VERSION 5.7 ;
  NOWIREEXTENSIONATPIN ON ;
  DIVIDERCHAR "/" ;
  BUSBITCHARS "[]" ;
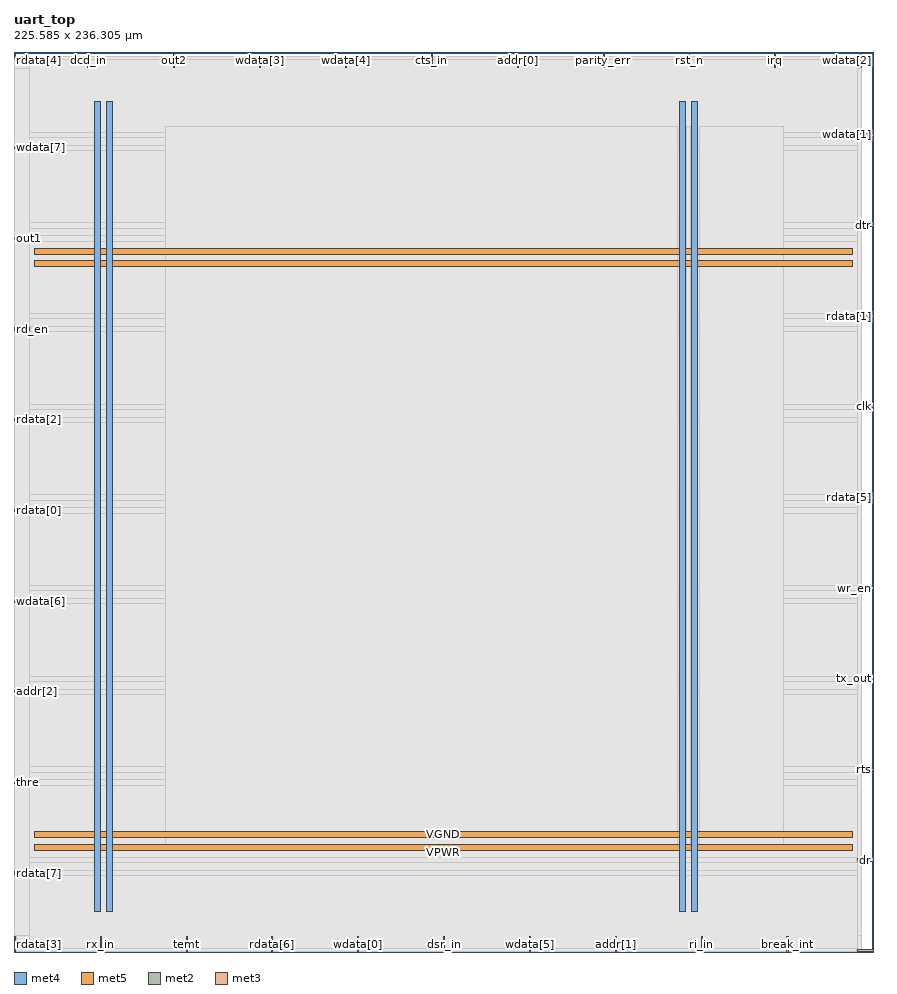
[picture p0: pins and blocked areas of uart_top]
MACRO uart_top
  CLASS BLOCK ;
  FOREIGN uart_top ;
  ORIGIN 0.000 0.000 ;
  SIZE 225.585 BY 236.305 ;
  PIN VGND
    DIRECTION INOUT ;
    USE GROUND ;
    PORT
      LAYER met4 ;
        RECT 24.340 10.640 25.940 223.280 ;
    END
    PORT
      LAYER met4 ;
        RECT 177.940 10.640 179.540 223.280 ;
    END
    PORT
      LAYER met5 ;
        RECT 5.280 30.030 220.120 31.630 ;
    END
    PORT
      LAYER met5 ;
        RECT 5.280 183.210 220.120 184.810 ;
    END
  END VGND
  PIN VPWR
    DIRECTION INOUT ;
    USE POWER ;
    PORT
      LAYER met4 ;
        RECT 21.040 10.640 22.640 223.280 ;
    END
    PORT
      LAYER met4 ;
        RECT 174.640 10.640 176.240 223.280 ;
    END
    PORT
      LAYER met5 ;
        RECT 5.280 26.730 220.120 28.330 ;
    END
    PORT
      LAYER met5 ;
        RECT 5.280 179.910 220.120 181.510 ;
    END
  END VPWR
  PIN addr[0]
    DIRECTION INPUT ;
    USE SIGNAL ;
    ANTENNAGATEAREA 0.159000 ;
    PORT
      LAYER met2 ;
        RECT 132.110 232.305 132.390 236.305 ;
    END
  END addr[0]
  PIN addr[1]
    DIRECTION INPUT ;
    USE SIGNAL ;
    ANTENNAGATEAREA 0.213000 ;
    PORT
      LAYER met2 ;
        RECT 157.870 0.000 158.150 4.000 ;
    END
  END addr[1]
  PIN addr[2]
    DIRECTION INPUT ;
    USE SIGNAL ;
    ANTENNAGATEAREA 0.159000 ;
    PORT
      LAYER met3 ;
        RECT 0.000 68.040 4.000 68.640 ;
    END
  END addr[2]
  PIN break_int
    DIRECTION OUTPUT TRISTATE ;
    USE SIGNAL ;
    ANTENNADIFFAREA 0.795200 ;
    PORT
      LAYER met2 ;
        RECT 202.950 0.000 203.230 4.000 ;
    END
  END break_int
  PIN clk
    DIRECTION INPUT ;
    USE SIGNAL ;
    ANTENNAGATEAREA 0.852000 ;
    PORT
      LAYER met3 ;
        RECT 221.585 142.840 225.585 143.440 ;
    END
  END clk
  PIN cts_in
    DIRECTION INPUT ;
    USE SIGNAL ;
    PORT
      LAYER met2 ;
        RECT 109.570 232.305 109.850 236.305 ;
    END
  END cts_in
  PIN dcd_in
    DIRECTION INPUT ;
    USE SIGNAL ;
    PORT
      LAYER met2 ;
        RECT 19.410 232.305 19.690 236.305 ;
    END
  END dcd_in
  PIN dr
    DIRECTION OUTPUT TRISTATE ;
    USE SIGNAL ;
    ANTENNADIFFAREA 0.445500 ;
    PORT
      LAYER met3 ;
        RECT 221.585 23.840 225.585 24.440 ;
    END
  END dr
  PIN dsr_in
    DIRECTION INPUT ;
    USE SIGNAL ;
    PORT
      LAYER met2 ;
        RECT 112.790 0.000 113.070 4.000 ;
    END
  END dsr_in
  PIN dtr
    DIRECTION OUTPUT TRISTATE ;
    USE SIGNAL ;
    ANTENNADIFFAREA 0.445500 ;
    PORT
      LAYER met3 ;
        RECT 221.585 190.440 225.585 191.040 ;
    END
  END dtr
  PIN framing_err
    DIRECTION OUTPUT TRISTATE ;
    USE SIGNAL ;
    ANTENNADIFFAREA 0.795200 ;
    PORT
      LAYER met3 ;
        RECT 221.585 0.040 225.585 0.640 ;
    END
  END framing_err
  PIN irq
    DIRECTION OUTPUT TRISTATE ;
    USE SIGNAL ;
    ANTENNADIFFAREA 0.795200 ;
    PORT
      LAYER met2 ;
        RECT 199.730 232.305 200.010 236.305 ;
    END
  END irq
  PIN out1
    DIRECTION OUTPUT TRISTATE ;
    USE SIGNAL ;
    ANTENNADIFFAREA 0.795200 ;
    PORT
      LAYER met3 ;
        RECT 0.000 187.040 4.000 187.640 ;
    END
  END out1
  PIN out2
    DIRECTION OUTPUT TRISTATE ;
    USE SIGNAL ;
    ANTENNADIFFAREA 0.795200 ;
    PORT
      LAYER met2 ;
        RECT 41.950 232.305 42.230 236.305 ;
    END
  END out2
  PIN parity_err
    DIRECTION OUTPUT TRISTATE ;
    USE SIGNAL ;
    ANTENNADIFFAREA 0.795200 ;
    PORT
      LAYER met2 ;
        RECT 154.650 232.305 154.930 236.305 ;
    END
  END parity_err
  PIN rd_en
    DIRECTION INPUT ;
    USE SIGNAL ;
    ANTENNAGATEAREA 0.213000 ;
    PORT
      LAYER met3 ;
        RECT 0.000 163.240 4.000 163.840 ;
    END
  END rd_en
  PIN rdata[0]
    DIRECTION OUTPUT TRISTATE ;
    USE SIGNAL ;
    ANTENNADIFFAREA 0.795200 ;
    PORT
      LAYER met3 ;
        RECT 0.000 115.640 4.000 116.240 ;
    END
  END rdata[0]
  PIN rdata[1]
    DIRECTION OUTPUT TRISTATE ;
    USE SIGNAL ;
    ANTENNADIFFAREA 0.445500 ;
    PORT
      LAYER met3 ;
        RECT 221.585 166.640 225.585 167.240 ;
    END
  END rdata[1]
  PIN rdata[2]
    DIRECTION OUTPUT TRISTATE ;
    USE SIGNAL ;
    ANTENNADIFFAREA 0.795200 ;
    PORT
      LAYER met3 ;
        RECT 0.000 139.440 4.000 140.040 ;
    END
  END rdata[2]
  PIN rdata[3]
    DIRECTION OUTPUT TRISTATE ;
    USE SIGNAL ;
    ANTENNADIFFAREA 0.795200 ;
    PORT
      LAYER met2 ;
        RECT 0.090 0.000 0.370 4.000 ;
    END
  END rdata[3]
  PIN rdata[4]
    DIRECTION OUTPUT TRISTATE ;
    USE SIGNAL ;
    ANTENNADIFFAREA 0.795200 ;
    PORT
      LAYER met3 ;
        RECT 0.000 234.640 4.000 235.240 ;
    END
  END rdata[4]
  PIN rdata[5]
    DIRECTION OUTPUT TRISTATE ;
    USE SIGNAL ;
    ANTENNADIFFAREA 0.445500 ;
    PORT
      LAYER met3 ;
        RECT 221.585 119.040 225.585 119.640 ;
    END
  END rdata[5]
  PIN rdata[6]
    DIRECTION OUTPUT TRISTATE ;
    USE SIGNAL ;
    ANTENNADIFFAREA 0.795200 ;
    PORT
      LAYER met2 ;
        RECT 67.710 0.000 67.990 4.000 ;
    END
  END rdata[6]
  PIN rdata[7]
    DIRECTION OUTPUT TRISTATE ;
    USE SIGNAL ;
    ANTENNADIFFAREA 0.795200 ;
    PORT
      LAYER met3 ;
        RECT 0.000 20.440 4.000 21.040 ;
    END
  END rdata[7]
  PIN ri_in
    DIRECTION INPUT ;
    USE SIGNAL ;
    PORT
      LAYER met2 ;
        RECT 180.410 0.000 180.690 4.000 ;
    END
  END ri_in
  PIN rst_n
    DIRECTION INPUT ;
    USE SIGNAL ;
    ANTENNAGATEAREA 0.213000 ;
    PORT
      LAYER met2 ;
        RECT 177.190 232.305 177.470 236.305 ;
    END
  END rst_n
  PIN rts
    DIRECTION OUTPUT TRISTATE ;
    USE SIGNAL ;
    ANTENNADIFFAREA 0.445500 ;
    PORT
      LAYER met3 ;
        RECT 221.585 47.640 225.585 48.240 ;
    END
  END rts
  PIN rx_in
    DIRECTION INPUT ;
    USE SIGNAL ;
    ANTENNAGATEAREA 0.213000 ;
    PORT
      LAYER met2 ;
        RECT 22.630 0.000 22.910 4.000 ;
    END
  END rx_in
  PIN temt
    DIRECTION OUTPUT TRISTATE ;
    USE SIGNAL ;
    ANTENNADIFFAREA 0.795200 ;
    PORT
      LAYER met2 ;
        RECT 45.170 0.000 45.450 4.000 ;
    END
  END temt
  PIN thre
    DIRECTION OUTPUT TRISTATE ;
    USE SIGNAL ;
    ANTENNADIFFAREA 0.795200 ;
    PORT
      LAYER met3 ;
        RECT 0.000 44.240 4.000 44.840 ;
    END
  END thre
  PIN tx_out
    DIRECTION OUTPUT TRISTATE ;
    USE SIGNAL ;
    ANTENNADIFFAREA 0.445500 ;
    PORT
      LAYER met3 ;
        RECT 221.585 71.440 225.585 72.040 ;
    END
  END tx_out
  PIN wdata[0]
    DIRECTION INPUT ;
    USE SIGNAL ;
    ANTENNAGATEAREA 0.159000 ;
    PORT
      LAYER met2 ;
        RECT 90.250 0.000 90.530 4.000 ;
    END
  END wdata[0]
  PIN wdata[1]
    DIRECTION INPUT ;
    USE SIGNAL ;
    ANTENNAGATEAREA 0.213000 ;
    PORT
      LAYER met3 ;
        RECT 221.585 214.240 225.585 214.840 ;
    END
  END wdata[1]
  PIN wdata[2]
    DIRECTION INPUT ;
    USE SIGNAL ;
    ANTENNAGATEAREA 0.213000 ;
    PORT
      LAYER met2 ;
        RECT 222.270 232.305 222.550 236.305 ;
    END
  END wdata[2]
  PIN wdata[3]
    DIRECTION INPUT ;
    USE SIGNAL ;
    ANTENNAGATEAREA 0.213000 ;
    PORT
      LAYER met2 ;
        RECT 64.490 232.305 64.770 236.305 ;
    END
  END wdata[3]
  PIN wdata[4]
    DIRECTION INPUT ;
    USE SIGNAL ;
    ANTENNAGATEAREA 0.213000 ;
    PORT
      LAYER met2 ;
        RECT 87.030 232.305 87.310 236.305 ;
    END
  END wdata[4]
  PIN wdata[5]
    DIRECTION INPUT ;
    USE SIGNAL ;
    ANTENNAGATEAREA 0.159000 ;
    PORT
      LAYER met2 ;
        RECT 135.330 0.000 135.610 4.000 ;
    END
  END wdata[5]
  PIN wdata[6]
    DIRECTION INPUT ;
    USE SIGNAL ;
    ANTENNAGATEAREA 0.213000 ;
    PORT
      LAYER met3 ;
        RECT 0.000 91.840 4.000 92.440 ;
    END
  END wdata[6]
  PIN wdata[7]
    DIRECTION INPUT ;
    USE SIGNAL ;
    ANTENNAGATEAREA 0.213000 ;
    PORT
      LAYER met3 ;
        RECT 0.000 210.840 4.000 211.440 ;
    END
  END wdata[7]
  PIN wr_en
    DIRECTION INPUT ;
    USE SIGNAL ;
    ANTENNAGATEAREA 0.213000 ;
    PORT
      LAYER met3 ;
        RECT 221.585 95.240 225.585 95.840 ;
    END
  END wr_en
  OBS
      LAYER li1 ;
        RECT 5.520 10.795 219.880 223.125 ;
      LAYER met1 ;
        RECT 0.070 10.640 222.570 223.280 ;
      LAYER met2 ;
        RECT 0.100 232.025 19.130 235.125 ;
        RECT 19.970 232.025 41.670 235.125 ;
        RECT 42.510 232.025 64.210 235.125 ;
        RECT 65.050 232.025 86.750 235.125 ;
        RECT 87.590 232.025 109.290 235.125 ;
        RECT 110.130 232.025 131.830 235.125 ;
        RECT 132.670 232.025 154.370 235.125 ;
        RECT 155.210 232.025 176.910 235.125 ;
        RECT 177.750 232.025 199.450 235.125 ;
        RECT 200.290 232.025 221.990 235.125 ;
        RECT 0.100 4.280 222.540 232.025 ;
        RECT 0.650 0.155 22.350 4.280 ;
        RECT 23.190 0.155 44.890 4.280 ;
        RECT 45.730 0.155 67.430 4.280 ;
        RECT 68.270 0.155 89.970 4.280 ;
        RECT 90.810 0.155 112.510 4.280 ;
        RECT 113.350 0.155 135.050 4.280 ;
        RECT 135.890 0.155 157.590 4.280 ;
        RECT 158.430 0.155 180.130 4.280 ;
        RECT 180.970 0.155 202.670 4.280 ;
        RECT 203.510 0.155 222.540 4.280 ;
      LAYER met3 ;
        RECT 4.400 234.240 221.585 235.105 ;
        RECT 3.990 215.240 221.585 234.240 ;
        RECT 3.990 213.840 221.185 215.240 ;
        RECT 3.990 211.840 221.585 213.840 ;
        RECT 4.400 210.440 221.585 211.840 ;
        RECT 3.990 191.440 221.585 210.440 ;
        RECT 3.990 190.040 221.185 191.440 ;
        RECT 3.990 188.040 221.585 190.040 ;
        RECT 4.400 186.640 221.585 188.040 ;
        RECT 3.990 167.640 221.585 186.640 ;
        RECT 3.990 166.240 221.185 167.640 ;
        RECT 3.990 164.240 221.585 166.240 ;
        RECT 4.400 162.840 221.585 164.240 ;
        RECT 3.990 143.840 221.585 162.840 ;
        RECT 3.990 142.440 221.185 143.840 ;
        RECT 3.990 140.440 221.585 142.440 ;
        RECT 4.400 139.040 221.585 140.440 ;
        RECT 3.990 120.040 221.585 139.040 ;
        RECT 3.990 118.640 221.185 120.040 ;
        RECT 3.990 116.640 221.585 118.640 ;
        RECT 4.400 115.240 221.585 116.640 ;
        RECT 3.990 96.240 221.585 115.240 ;
        RECT 3.990 94.840 221.185 96.240 ;
        RECT 3.990 92.840 221.585 94.840 ;
        RECT 4.400 91.440 221.585 92.840 ;
        RECT 3.990 72.440 221.585 91.440 ;
        RECT 3.990 71.040 221.185 72.440 ;
        RECT 3.990 69.040 221.585 71.040 ;
        RECT 4.400 67.640 221.585 69.040 ;
        RECT 3.990 48.640 221.585 67.640 ;
        RECT 3.990 47.240 221.185 48.640 ;
        RECT 3.990 45.240 221.585 47.240 ;
        RECT 4.400 43.840 221.585 45.240 ;
        RECT 3.990 24.840 221.585 43.840 ;
        RECT 3.990 23.440 221.185 24.840 ;
        RECT 3.990 21.440 221.585 23.440 ;
        RECT 4.400 20.040 221.585 21.440 ;
        RECT 3.990 1.040 221.585 20.040 ;
        RECT 3.990 0.175 221.185 1.040 ;
      LAYER met4 ;
        RECT 39.855 28.055 174.240 216.745 ;
        RECT 176.640 28.055 177.540 216.745 ;
        RECT 179.940 28.055 202.105 216.745 ;
  END
END uart_top
END LIBRARY

